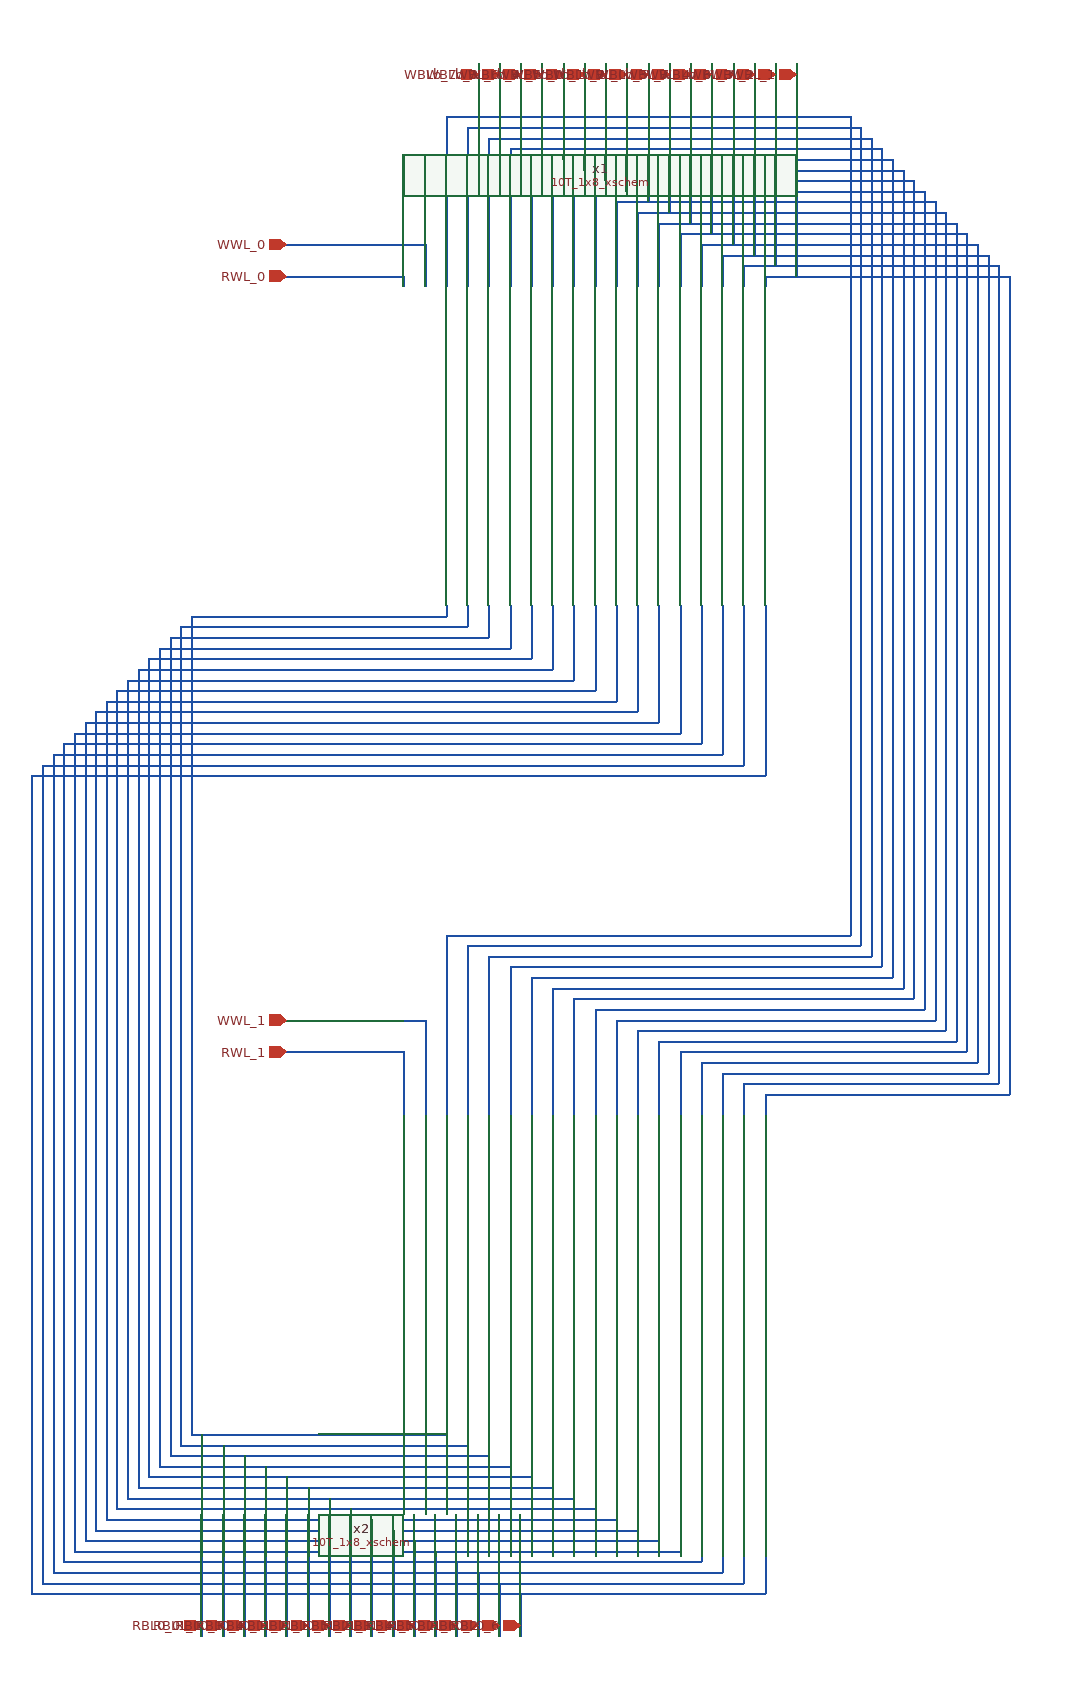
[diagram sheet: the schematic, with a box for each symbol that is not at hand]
v {xschem version=3.0.0 file_version=1.2 }
G {}
K {}
V {}
S {}
E {}
N 1600 -1930 1730 -1930 {
lab=WWL_0}
N 1730 -1930 1730 -1890 {
lab=WWL_0}
N 1600 -1900 1710 -1900 {
lab=RWL_0}
N 1710 -1900 1710 -1890 {
lab=RWL_0}
N 1590 -1200 1730 -1200 {
lab=WWL_1}
N 1730 -1200 1730 -1160 {
lab=WWL_1}
N 1600 -1170 1710 -1170 {
lab=RWL_1}
N 1710 -1120 1710 -1110 {
lab=RWL_1}
N 1750 -1280 1750 -1160 {
lab=WBLb_7}
N 1750 -1280 2130 -1280 {
lab=WBLb_7}
N 1770 -1270 1770 -1160 {
lab=WBLb_3}
N 1770 -1270 2140 -1270 {
lab=WBLb_3}
N 1790 -1260 1790 -1160 {
lab=WBL_6}
N 1790 -1260 2150 -1260 {
lab=WBL_6}
N 1810 -1250 1810 -1160 {
lab=WBLb_4}
N 1810 -1250 2160 -1250 {
lab=WBLb_4}
N 1830 -1240 1830 -1160 {
lab=WBL_5}
N 1830 -1240 2170 -1240 {
lab=WBL_5}
N 1850 -1230 1850 -1160 {
lab=WBLb_0}
N 1850 -1230 2180 -1230 {
lab=WBLb_0}
N 1870 -1220 1870 -1160 {
lab=WBLb_1}
N 1870 -1220 2190 -1220 {
lab=WBLb_1}
N 1890 -1210 1890 -1160 {
lab=WBLb_2}
N 1890 -1210 2200 -1210 {
lab=WBLb_2}
N 1910 -1200 1910 -1160 {
lab=WBL_0}
N 1910 -1200 2210 -1200 {
lab=WBL_0}
N 1930 -1190 1930 -1160 {
lab=WBLb_5}
N 1930 -1190 2220 -1190 {
lab=WBLb_5}
N 1950 -1180 2230 -1180 {
lab=WBL_7}
N 1970 -1120 1970 -1110 {
lab=WBL_4}
N 1970 -1170 2240 -1170 {
lab=WBL_4}
N 1990 -1160 1990 -1110 {
lab=WBLb_6}
N 1990 -1160 2250 -1160 {
lab=WBLb_6}
N 2010 -1150 2010 -1110 {
lab=WBL_3}
N 2010 -1150 2260 -1150 {
lab=WBL_3}
N 2030 -1140 2030 -1110 {
lab=WBL_2}
N 2030 -1140 2270 -1140 {
lab=WBL_2}
N 2050 -1130 2050 -1110 {
lab=WWL_0}
N 2050 -1130 2280 -1130 {
lab=WWL_0}
N 1970 -1170 1970 -1120 {
lab=WBL_4}
N 1950 -1180 1950 -1120 {
lab=WBL_7}
N 1950 -1120 1950 -1110 {
lab=WBL_7}
N 1930 -1160 1930 -1110 {
lab=WBLb_5}
N 1910 -1160 1910 -1110 {
lab=WBL_0}
N 1890 -1160 1890 -1110 {
lab=WBLb_2}
N 1870 -1160 1870 -1110 {
lab=WBLb_1}
N 1850 -1160 1850 -1110 {
lab=WBLb_0}
N 1830 -1160 1830 -1110 {
lab=WBL_5}
N 1810 -1160 1810 -1110 {
lab=WBLb_4}
N 1790 -1160 1790 -1110 {
lab=WBL_6}
N 1770 -1160 1770 -1110 {
lab=WBLb_3}
N 1750 -1160 1750 -1110 {
lab=WBLb_7}
N 1730 -1160 1730 -1110 {
lab=WWL_1}
N 1710 -1170 1710 -1120 {
lab=RWL_1}
N 2050 -1900 2050 -1890 {
lab=WWL_0}
N 2030 -1910 2030 -1890 {
lab=WBL_2}
N 2010 -1920 2010 -1890 {
lab=WBL_3}
N 2050 -1900 2280 -1900 {
lab=WWL_0}
N 2280 -1900 2280 -1130 {
lab=WWL_0}
N 2270 -1910 2270 -1140 {
lab=WBL_2}
N 2030 -1910 2270 -1910 {
lab=WBL_2}
N 2010 -1920 2260 -1920 {
lab=WBL_3}
N 1990 -1930 1990 -1890 {
lab=WBLb_6}
N 1990 -1930 2250 -1930 {
lab=WBLb_6}
N 1970 -1940 1970 -1890 {
lab=WBL_4}
N 1970 -1940 2240 -1940 {
lab=WBL_4}
N 1950 -1950 1950 -1890 {
lab=WBL_7}
N 1950 -1950 2230 -1950 {
lab=WBL_7}
N 1930 -1960 1930 -1890 {
lab=WBLb_5}
N 1930 -1960 2220 -1960 {
lab=WBLb_5}
N 1910 -1970 1910 -1900 {
lab=WBL_0}
N 1910 -1970 2210 -1970 {
lab=WBL_0}
N 1890 -1980 1890 -1890 {
lab=WBLb_2}
N 1890 -1980 2200 -1980 {
lab=WBLb_2}
N 1870 -1990 1870 -1900 {
lab=WBLb_1}
N 1870 -1990 2190 -1990 {
lab=WBLb_1}
N 1910 -1900 1910 -1890 {
lab=WBL_0}
N 1870 -1900 1870 -1890 {
lab=WBLb_1}
N 1850 -2000 1850 -1890 {
lab=WBLb_0}
N 1850 -2000 2180 -2000 {
lab=WBLb_0}
N 1830 -2010 1830 -1890 {
lab=WBL_5}
N 1830 -2010 2170 -2010 {
lab=WBL_5}
N 1810 -2020 1810 -1890 {
lab=WBLb_4}
N 1810 -2020 2160 -2020 {
lab=WBLb_4}
N 1790 -2030 1790 -1890 {
lab=WBL_6}
N 1790 -2030 2150 -2030 {
lab=WBL_6}
N 1770 -2040 1770 -1890 {
lab=WBLb_3}
N 1770 -2040 2140 -2040 {
lab=WBLb_3}
N 1750 -2050 1750 -1890 {
lab=WBLb_7}
N 1750 -2050 2130 -2050 {
lab=WBLb_7}
N 2130 -2050 2130 -1280 {
lab=WBLb_7}
N 2140 -2040 2140 -1270 {
lab=WBLb_3}
N 2150 -2030 2150 -1260 {
lab=WBL_6}
N 2160 -2020 2160 -1250 {
lab=WBLb_4}
N 2170 -2010 2170 -1240 {
lab=WBL_5}
N 2180 -2000 2180 -1230 {
lab=WBLb_0}
N 2190 -1990 2190 -1220 {
lab=WBLb_1}
N 2200 -1980 2200 -1210 {
lab=WBLb_2}
N 2210 -1970 2210 -1200 {
lab=WBL_0}
N 2220 -1960 2220 -1190 {
lab=WBLb_5}
N 2230 -1950 2230 -1180 {
lab=WBL_7}
N 2240 -1940 2240 -1170 {
lab=WBL_4}
N 2250 -1930 2250 -1160 {
lab=WBLb_6}
N 2260 -1920 2260 -1150 {
lab=WBL_3}
N 1750 -1590 1750 -1580 {
lab=RBL0_0}
N 1510 -1580 1750 -1580 {
lab=RBL0_0}
N 1770 -1590 1770 -1570 {
lab=RBL1_0}
N 1500 -1570 1770 -1570 {
lab=RBL1_0}
N 1790 -1590 1790 -1560 {
lab=RBL0_3}
N 1490 -1560 1790 -1560 {
lab=RBL0_3}
N 1810 -1590 1810 -1550 {
lab=RBL0_4}
N 1480 -1550 1810 -1550 {
lab=RBL0_4}
N 1830 -1590 1830 -1540 {
lab=RBL0_1}
N 1470 -1540 1830 -1540 {
lab=RBL0_1}
N 1850 -1590 1850 -1530 {
lab=RBL1_7}
N 1460 -1530 1850 -1530 {
lab=RBL1_7}
N 1870 -1590 1870 -1520 {
lab=RBL1_1}
N 1450 -1520 1870 -1520 {
lab=RBL1_1}
N 1890 -1590 1890 -1510 {
lab=RBL0_5}
N 1440 -1510 1890 -1510 {
lab=RBL0_5}
N 1910 -1590 1910 -1500 {
lab=RBL1_2}
N 1430 -1500 1910 -1500 {
lab=RBL1_2}
N 1930 -1590 1930 -1490 {
lab=RBL1_3}
N 1420 -1490 1930 -1490 {
lab=RBL1_3}
N 1950 -1590 1950 -1480 {
lab=RBL1_4}
N 1410 -1480 1950 -1480 {
lab=RBL1_4}
N 1970 -1590 1970 -1470 {
lab=RBL1_5}
N 1400 -1470 1970 -1470 {
lab=RBL1_5}
N 1990 -1590 1990 -1460 {
lab=RBL0_7}
N 1390 -1460 1990 -1460 {
lab=RBL0_7}
N 2010 -1590 2010 -1450 {
lab=RBL1_6}
N 1380 -1450 2010 -1450 {
lab=RBL1_6}
N 2030 -1590 2030 -1440 {
lab=RBL0_2}
N 1370 -1440 2030 -1440 {
lab=RBL0_2}
N 2050 -1590 2050 -1430 {
lab=RBL0_6}
N 1360 -1430 2050 -1430 {
lab=RBL0_6}
N 1510 -1580 1510 -820 {
lab=RBL0_0}
N 1510 -820 1510 -810 {
lab=RBL0_0}
N 1510 -810 1750 -810 {
lab=RBL0_0}
N 1770 -810 1770 -800 {
lab=RBL1_0}
N 1500 -800 1770 -800 {
lab=RBL1_0}
N 1790 -810 1790 -790 {
lab=RBL0_3}
N 1490 -790 1790 -790 {
lab=RBL0_3}
N 1810 -810 1810 -780 {
lab=RBL0_4}
N 1490 -780 1810 -780 {
lab=RBL0_4}
N 1480 -780 1490 -780 {
lab=RBL0_4}
N 1830 -810 1830 -770 {
lab=RBL0_1}
N 1470 -770 1830 -770 {
lab=RBL0_1}
N 1850 -810 1850 -760 {
lab=RBL1_7}
N 1460 -760 1850 -760 {
lab=RBL1_7}
N 1870 -810 1870 -750 {
lab=RBL1_1}
N 1450 -750 1870 -750 {
lab=RBL1_1}
N 1890 -810 1890 -740 {
lab=RBL0_5}
N 1440 -740 1890 -740 {
lab=RBL0_5}
N 1910 -810 1910 -730 {
lab=RBL1_2}
N 1430 -730 1910 -730 {
lab=RBL1_2}
N 1930 -810 1930 -720 {
lab=RBL1_3}
N 1420 -720 1930 -720 {
lab=RBL1_3}
N 1950 -810 1950 -710 {
lab=RBL1_4}
N 1410 -710 1950 -710 {
lab=RBL1_4}
N 1970 -810 1970 -700 {
lab=RBL1_5}
N 1400 -700 1970 -700 {
lab=RBL1_5}
N 1990 -810 1990 -690 {
lab=RBL0_7}
N 1390 -690 1990 -690 {
lab=RBL0_7}
N 2010 -810 2010 -680 {
lab=RBL1_6}
N 1380 -680 2010 -680 {
lab=RBL1_6}
N 2030 -810 2030 -670 {
lab=RBL0_2}
N 1370 -670 2030 -670 {
lab=RBL0_2}
N 2050 -810 2050 -660 {
lab=RBL0_6}
N 1360 -660 2050 -660 {
lab=RBL0_6}
N 1360 -1430 1360 -660 {
lab=RBL0_6}
N 1370 -1440 1370 -670 {
lab=RBL0_2}
N 1380 -1450 1380 -680 {
lab=RBL1_6}
N 1390 -1460 1390 -690 {
lab=RBL0_7}
N 1400 -1470 1400 -700 {
lab=RBL1_5}
N 1410 -1480 1410 -710 {
lab=RBL1_4}
N 1420 -1490 1420 -720 {
lab=RBL1_3}
N 1430 -1500 1430 -730 {
lab=RBL1_2}
N 1440 -1510 1440 -740 {
lab=RBL0_5}
N 1450 -1520 1450 -750 {
lab=RBL1_1}
N 1460 -1530 1460 -760 {
lab=RBL1_7}
N 1470 -1540 1470 -770 {
lab=RBL0_1}
N 1480 -1550 1480 -780 {
lab=RBL0_4}
N 1490 -1560 1490 -790 {
lab=RBL0_3}
N 1500 -1570 1500 -800 {
lab=RBL1_0}
N 1520 -810 1520 -620 {
lab=RBL0_0}
N 1540 -800 1540 -620 {
lab=RBL1_0}
N 1560 -790 1560 -620 {
lab=RBL0_3}
N 1580 -780 1580 -620 {
lab=RBL0_4}
N 1600 -770 1600 -620 {
lab=RBL0_1}
N 1620 -760 1620 -620 {
lab=RBL1_7}
N 1640 -750 1640 -620 {
lab=RBL1_1}
N 1660 -740 1660 -620 {
lab=RBL0_5}
N 1680 -730 1680 -620 {
lab=RBL1_2}
N 1700 -720 1700 -630 {
lab=RBL1_3}
N 1700 -630 1700 -620 {
lab=RBL1_3}
N 1720 -710 1720 -620 {
lab=RBL1_4}
N 1740 -700 1740 -620 {
lab=RBL1_5}
N 1760 -690 1760 -620 {
lab=RBL0_7}
N 1780 -680 1780 -620 {
lab=RBL1_6}
N 1800 -670 1800 -620 {
lab=RBL0_2}
N 1820 -660 1820 -620 {
lab=RBL0_6}
N 1780 -2100 1780 -2050 {
lab=WBLb_7}
N 1800 -2100 1800 -2040 {
lab=WBLb_3}
N 1820 -2100 1820 -2030 {
lab=WBL_6}
N 1840 -2100 1840 -2020 {
lab=WBLb_4}
N 1860 -2100 1860 -2010 {
lab=WBL_5}
N 1880 -2100 1880 -2000 {
lab=WBLb_0}
N 1900 -2100 1900 -1990 {
lab=WBLb_1}
N 1920 -2100 1920 -1980 {
lab=WBLb_2}
N 1940 -2100 1940 -1970 {
lab=WBL_0}
N 1960 -2100 1960 -1960 {
lab=WBLb_5}
N 1980 -2100 1980 -1950 {
lab=WBL_7}
N 2000 -2100 2000 -1940 {
lab=WBL_4}
N 2020 -2100 2020 -1930 {
lab=WBLb_6}
N 2040 -2100 2040 -1920 {
lab=WBL_3}
N 2060 -2100 2060 -1910 {
lab=WBL_2}
N 2080 -2100 2080 -1900 {
lab=WWL_0}
C {/home/abishek/SRAM_WORK/osu-toy-sram/xschem/10T_1x8_xschem.sym} 1880 -1740 1 0 {name=x1 VDD=VDD GND=GND}
C {/home/abishek/SRAM_WORK/osu-toy-sram/xschem/10T_1x8_xschem.sym} 1880 -960 1 0 {name=x2 VDD=VDD GND=GND}
C {devices/ipin.sym} 1600 -1930 0 0 {name=l2 sig_type=std_logic lab=WWL_0}
C {devices/ipin.sym} 1600 -1900 0 0 {name=l1 sig_type=std_logic lab=RWL_0}
C {devices/ipin.sym} 1600 -1200 0 0 {name=l3 sig_type=std_logic lab=WWL_1}
C {devices/ipin.sym} 1600 -1170 0 0 {name=l4 sig_type=std_logic lab=RWL_1}
C {devices/ipin.sym} 1520 -630 3 0 {name=l5 sig_type=std_logic lab=RBL0_0}
C {devices/ipin.sym} 1540 -630 3 0 {name=l6 sig_type=std_logic lab=RBL1_0}
C {devices/ipin.sym} 1560 -630 3 0 {name=l7 sig_type=std_logic lab=RBL0_3}
C {devices/ipin.sym} 1580 -630 3 0 {name=l8 sig_type=std_logic lab=RBL0_4}
C {devices/ipin.sym} 1600 -630 3 0 {name=l9 sig_type=std_logic lab=RBL0_1}
C {devices/ipin.sym} 1620 -630 3 0 {name=l10 sig_type=std_logic lab=RBL1_7}
C {devices/ipin.sym} 1640 -630 3 0 {name=l11 sig_type=std_logic lab=RBL1_1}
C {devices/ipin.sym} 1660 -630 3 0 {name=l12 sig_type=std_logic lab=RBL0_5}
C {devices/ipin.sym} 1680 -630 3 0 {name=l13 sig_type=std_logic lab=RBL1_2}
C {devices/ipin.sym} 1700 -630 3 0 {name=l14 sig_type=std_logic lab=RBL1_3}
C {devices/ipin.sym} 1720 -630 3 0 {name=l15 sig_type=std_logic lab=RBL1_4}
C {devices/ipin.sym} 1740 -630 3 0 {name=l16 sig_type=std_logic lab=RBL1_5}
C {devices/ipin.sym} 1760 -630 3 0 {name=l17 sig_type=std_logic lab=RBL0_7}
C {devices/ipin.sym} 1780 -630 3 0 {name=l18 sig_type=std_logic lab=RBL1_6}
C {devices/ipin.sym} 1800 -630 3 0 {name=l19 sig_type=std_logic lab=RBL0_2}
C {devices/ipin.sym} 1820 -630 3 0 {name=l20 sig_type=std_logic lab=RBL0_6}
C {devices/ipin.sym} 1780 -2090 1 0 {name=l21 sig_type=std_logic lab=WBLb_7}
C {devices/ipin.sym} 1800 -2090 1 0 {name=l22 sig_type=std_logic lab=WBLb_3}
C {devices/ipin.sym} 1820 -2090 1 0 {name=l23 sig_type=std_logic lab=WBL_6}
C {devices/ipin.sym} 1840 -2090 1 0 {name=l24 sig_type=std_logic lab=WBLb_4}
C {devices/ipin.sym} 1860 -2090 1 0 {name=l25 sig_type=std_logic lab=WBL_5}
C {devices/ipin.sym} 1880 -2090 1 0 {name=l26 sig_type=std_logic lab=WBLb_0}
C {devices/ipin.sym} 1900 -2090 1 0 {name=l27 sig_type=std_logic lab=WBLb_1}
C {devices/ipin.sym} 1920 -2090 1 0 {name=l28 sig_type=std_logic lab=WBLb_2}
C {devices/ipin.sym} 1940 -2090 1 0 {name=l29 sig_type=std_logic lab=WBL_0}
C {devices/ipin.sym} 1960 -2090 1 0 {name=l30 sig_type=std_logic lab=WBLb_5}
C {devices/ipin.sym} 1980 -2090 1 0 {name=l31 sig_type=std_logic lab=WBL_7}
C {devices/ipin.sym} 2000 -2090 1 0 {name=l32 sig_type=std_logic lab=WBL_4}
C {devices/ipin.sym} 2020 -2090 1 0 {name=l33 sig_type=std_logic lab=WBLb_6}
C {devices/ipin.sym} 2040 -2090 1 0 {name=l34 sig_type=std_logic lab=WBL_3}
C {devices/ipin.sym} 2060 -2090 1 0 {name=l35 sig_type=std_logic lab=WBL_2}
C {devices/ipin.sym} 2080 -2090 1 0 {name=l36 sig_type=std_logic lab=WBL_1}
